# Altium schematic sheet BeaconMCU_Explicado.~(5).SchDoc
size A4

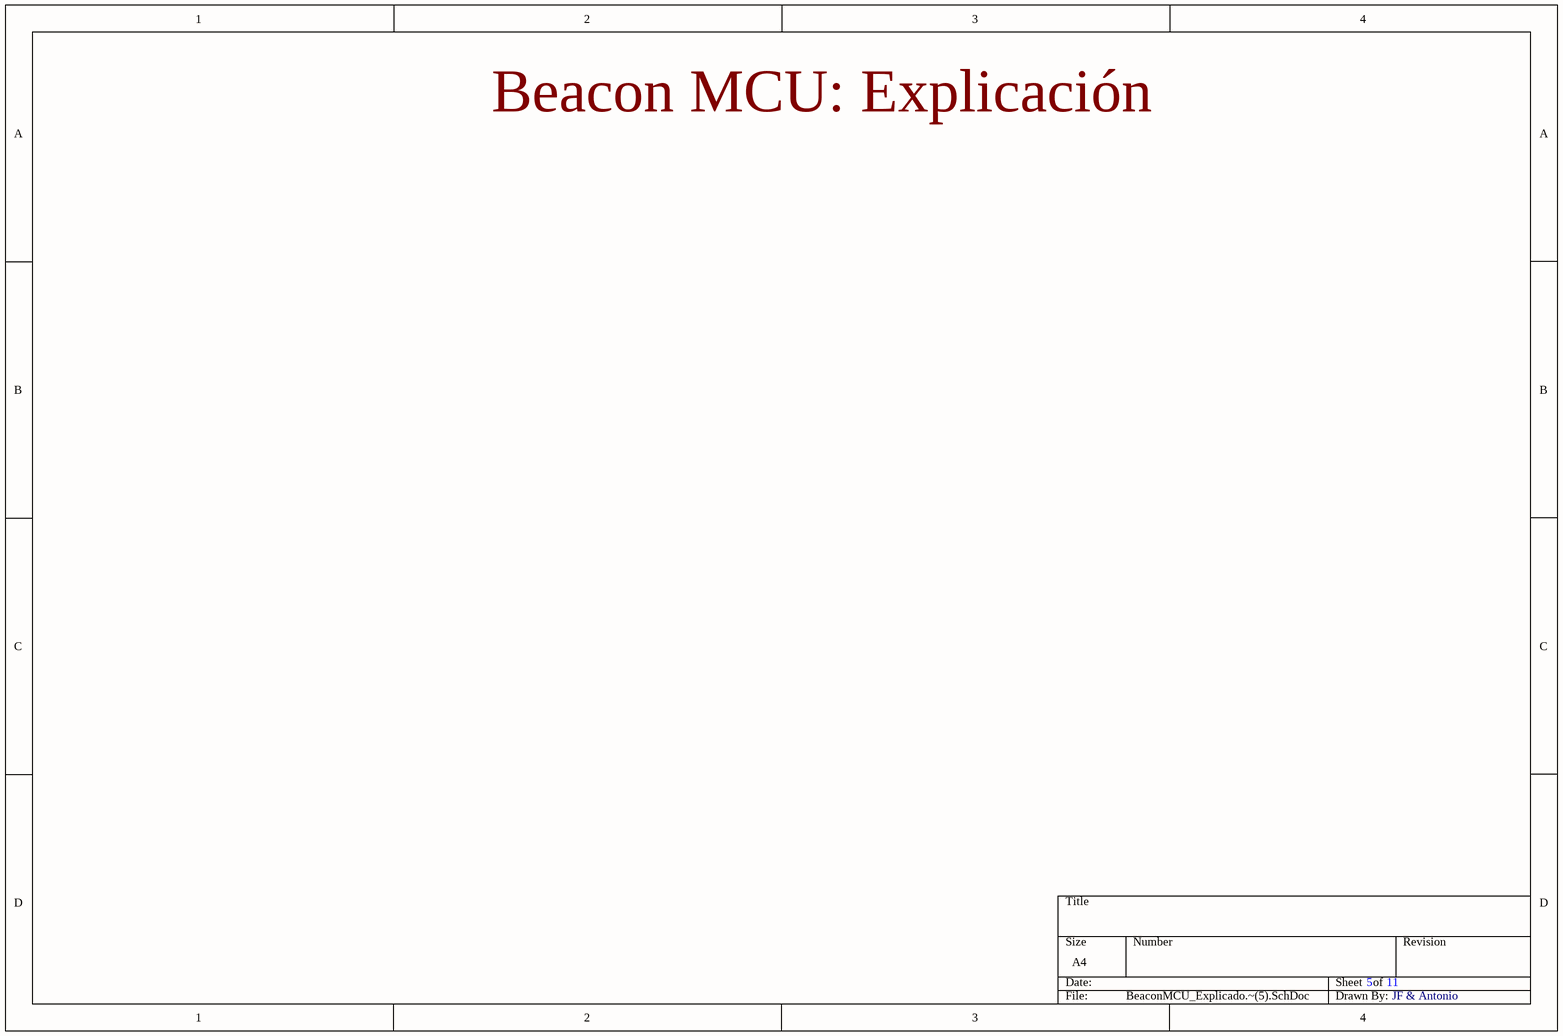
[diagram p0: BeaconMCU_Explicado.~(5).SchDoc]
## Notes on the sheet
- Beacon MCU: Explicación
- 5
- 11
- JF & Antonio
